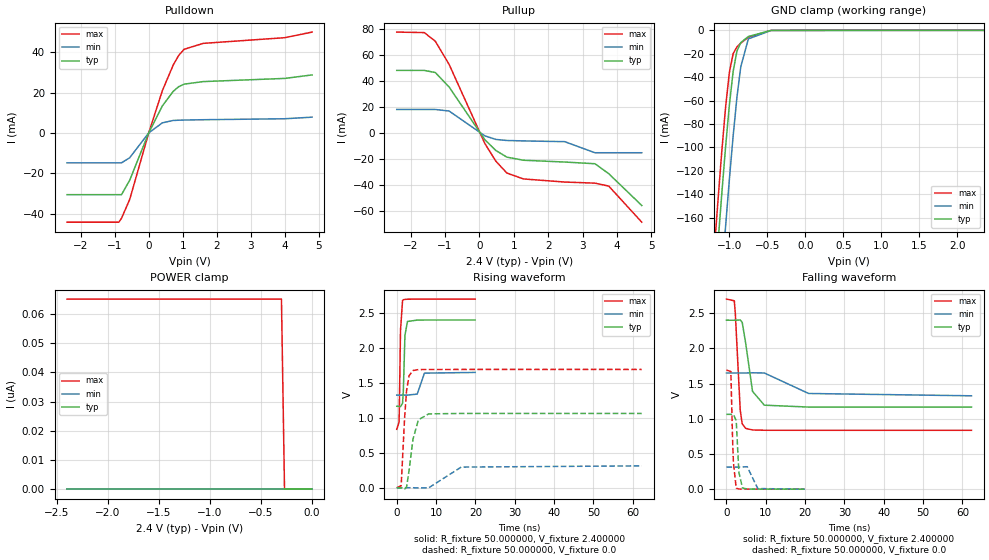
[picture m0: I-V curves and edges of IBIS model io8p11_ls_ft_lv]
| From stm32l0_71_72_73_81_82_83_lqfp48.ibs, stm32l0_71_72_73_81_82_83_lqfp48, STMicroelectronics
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|   Model io8p11_ls_ft_lv
[Model]  io8p11_ls_ft_lv
Model_type I/O
Polarity   Non-Inverting
Enable   Active-Low
Vinl =   0.720000V
Vinh =   1.680000V
Vmeas =  1.200000V
Cref =   50.000000pF
Rref =   100.000000M
Vref =   0.0V
C_comp   4.521100pF   4.438000pF   4.578000pF
[Temperature Range]   25.000000   0.105000k   -40.000000
[Pullup Reference]   2.400000V   1.650000V   2.700000V
[Pulldown Reference]   0.0V   0.0V   0.0V
[POWER Clamp Reference]   2.400000V   1.650000V   2.700000V
[GND Clamp Reference]   0.0V   0.0V   0.0V
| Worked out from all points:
|   slope of the pulldown table from 0 to 0.36 V, typ, clamps not added: 29.5 ohm
|   slope of the pullup table from 0 to 0.36 V, typ, clamps not added: 33.2 ohm
|   GND clamp passes 1 mA (typ) near -0.59 V on its own axis
|   rising waveform, R_fixture 50.000000, V_fixture 2.400000: 20-80 % time 364ps typ, 687ps min, 304ps max; typ from 1.17 V to 2.4 V
|   rising waveform, R_fixture 50.000000, V_fixture 0.0: 20-80 % time 1.63ns typ, 3.85ns min, 985ps max; typ from 0 V to 1.06 V
|   falling waveform, R_fixture 50.000000, V_fixture 2.400000: 20-80 % time 1.82ns typ, 5.38ns min, 983ps max; typ from 2.4 V to 1.17 V
|   falling waveform, R_fixture 50.000000, V_fixture 0.0: 20-80 % time 623ps typ, 1.01ns min, 516ps max; typ from 1.06 V to 0 V
[Pulldown]
|Voltage   I(typ)   I(min)   I(max)
-2.4V     -30.64mA   -14.84mA   -44.29mA
-880mV    -30.64mA   -14.84mA   -44.29mA
-800mV    -30.64mA   -14.84mA   -42.37mA
-560mV    -23.52mA   -12.34mA   -33.09mA
0V        -765.2nA   -61.1nA    -2.527uA
400mV     13.38mA    4.998mA    20.91mA
720mV     20.62mA    6.178mA    33.69mA
880mV     22.92mA    6.307mA    38.42mA
1.04V     24.19mA    6.385mA    41.49mA
1.6V      25.46mA    6.544mA    44.42mA
4V        27.04mA    7.029mA    47.25mA
4.8V      28.77mA    7.818mA    50.02mA
[Pullup]
|Voltage   I(typ)   I(min)   I(max)
-2.4V     48.08mA    17.97mA    77.6mA
-1.6V     48.08mA    17.97mA    77.22mA
-1.28V    46.45mA    17.97mA    70.55mA
-880mV    35.36mA    16.81mA    52.79mA
160mV     -5.286mA   -2.324mA   -8.223mA
480mV     -13.62mA   -5.103mA   -21.86mA
800mV     -18.73mA   -5.909mA   -31mA
1.28V     -21.13mA   -6.237mA   -35.54mA
2.48V     -22.51mA   -6.82mA    -37.93mA
3.36V     -23.83mA   -15.36mA   -38.77mA
3.76V     -31.5mA    -15.36mA   -41.06mA
4.72V     -56mA      -15.36mA   -68.86mA
[GND_clamp]
|Voltage   I(typ)   I(min)   I(max)
-2.4V     -1.379A    -1.445A    -1.35A
-1.2V     -225.9mA   -297.5mA   -189.2mA
-1.15V    -182mA     -253.1mA   -145.3mA
-1.1V     -139.6mA   -209.7mA   -103.5mA
-1.05V    -99.61mA   -167.6mA   -65.7mA
-1V       -63.67mA   -127.3mA   -35.89mA
-950mV    -35mA      -89.93mA   -19.87mA
-900mV    -17.67mA   -57.01mA   -14.12mA
-850mV    -10.49mA   -31.18mA   -11mA
-750mV    -5.288mA   -7.322mA   -5.997mA
-450mV    -33.57uA   -87.56uA   -14.35uA
2.35V     0A         0A         0A
[POWER_clamp]
|Voltage   I(typ)   I(min)   I(max)
-2.4V     0A         0A         65.17nA
-300mV    0A         0A         65.17nA
-270mV    0A         0A         0A
0V        0A         0A         0A
[Ramp]
| variable   typ   min   max
dV/dt_r  0.63779/1.62062n   0.18781/3.85012n   1.01572/0.97957n
dV/dt_f  0.74034/1.81656n   0.19290/5.36100n   1.11788/0.98038n
R_load = 50.000000
[Rising Waveform]
R_fixture= 50.000000
V_fixture= 2.400000
V_fixture_min= 1.650000
V_fixture_max= 2.700000
|time   V(typ)   V(min)   V(max)
0s        1.166V     1.326V     836.1mV
600.6ps   1.165V     1.326V     938.7mV
961ps     1.161V     1.326V     2.256V
1.481ns   1.21V      1.326V     2.679V
1.682ns   1.391V     1.326V     2.69V
2.082ns   2.179V     1.326V     2.695V
2.723ns   2.379V     1.326V     2.698V
5.205ns   2.399V     1.34V      2.699V
7.047ns   2.4V       1.64V      2.7V
19.94ns   2.4V       1.65V      2.7V
[Rising Waveform]
R_fixture= 50.000000
V_fixture= 0.0
V_fixture_min= 0.0
V_fixture_max= 0.0
|time   V(typ)   V(min)   V(max)
0s        63.35uV    12.7uV     531.9uV
1.126ns   -151.4uV   9.592uV    28.26mV
2.002ns   -20.43mV   22.6uV     1.001V
2.503ns   11.78mV    99.47uV    1.389V
3.128ns   243.6mV    98.53uV    1.602V
4.129ns   694.2mV    62.84uV    1.677V
5.506ns   971.6mV    -2.233mV   1.691V
8.133ns   1.057V     -668uV     1.692V
16.39ns   1.063V     295.5mV    1.693V
62.31ns   1.063V     313mV      1.693V
[Falling Waveform]
R_fixture= 50.000000
V_fixture= 2.400000
V_fixture_min= 1.650000
V_fixture_max= 2.700000
|time   V(typ)   V(min)   V(max)
0s        2.4V       1.65V      2.7V
2.002ns   2.399V     1.65V      2.675V
2.252ns   2.4V       1.65V      2.5V
3.504ns   2.403V     1.65V      1.122V
4.004ns   2.371V     1.65V      928.6mV
4.88ns    2.076V     1.65V      863.9mV
6.632ns   1.389V     1.653V     840.9mV
9.635ns   1.193V     1.65V      836.7mV
20.9ns    1.166V     1.359V     836.2mV
62.31ns   1.166V     1.326V     836.1mV
[Falling Waveform]
R_fixture= 50.000000
V_fixture= 0.0
V_fixture_min= 0.0
V_fixture_max= 0.0
|time   V(typ)   V(min)   V(max)
0s        1.063V     313mV      1.693V
1.121ns   1.063V     313mV      1.67V
1.522ns   1.062V     313mV      774mV
1.762ns   1.064V     313mV      386.7mV
2.482ns   974.1mV    313mV      13.59mV
3.163ns   239.4mV    312.7mV    2.841mV
4.084ns   16.78mV    315.6mV    1.81mV
5.285ns   1.895mV    318.8mV    1.07mV
7.968ns   543.9uV    8.55mV     653.6uV
19.94ns   63.35uV    12.7uV     531.9uV
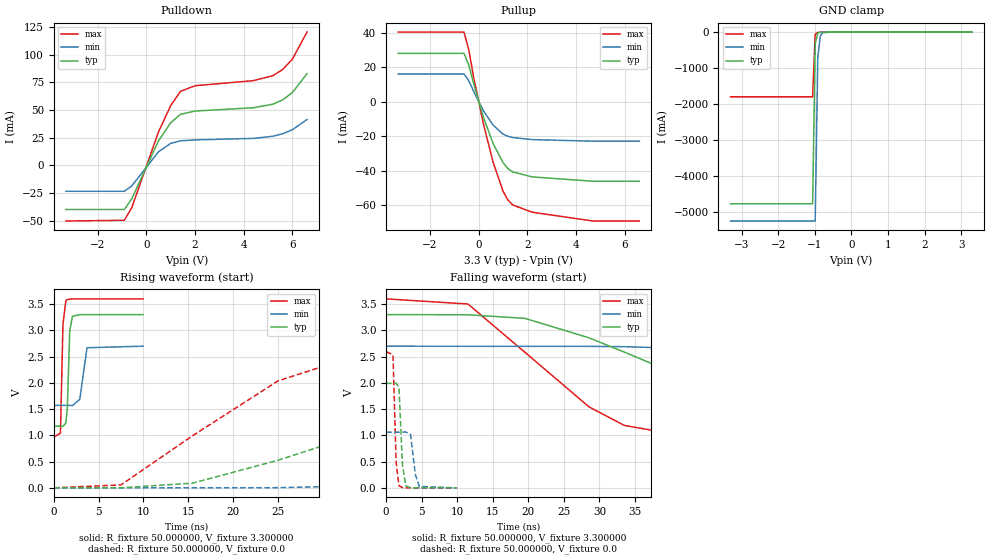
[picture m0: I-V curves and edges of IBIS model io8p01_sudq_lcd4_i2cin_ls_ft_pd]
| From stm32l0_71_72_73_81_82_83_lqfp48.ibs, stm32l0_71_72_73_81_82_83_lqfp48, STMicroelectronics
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|   Model io8p01_sudq_lcd4_i2cin_ls_ft_pd
[Model]  io8p01_sudq_lcd4_i2cin_ls_ft_pd
Model_type I/O
Polarity   Non-Inverting
Enable   Active-Low
Vinl =   0.990000V
Vinh =   2.310000V
Vmeas =  1.650000V
Cref =   50.000000pF
Rref =   100.000000M
Vref =   0.0V
C_comp   2.499500pF   2.460800pF   2.557800pF
[Temperature Range]   25.000000   0.125000k   -40.000000
[Pullup Reference]   3.300000V   2.700000V   3.600000V
[Pulldown Reference]   0.0V   0.0V   0.0V
[POWER Clamp Reference]   3.300000V   2.700000V   3.600000V
[GND Clamp Reference]   0.0V   0.0V   0.0V
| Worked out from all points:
|   slope of the pulldown table from 0 to 0.495 V, typ, clamps not added: 22.6 ohm
|   slope of the pullup table from 0 to 0.495 V, typ, clamps not added: 23.9 ohm
|   GND clamp passes 1 mA (typ) near -0.64 V on its own axis
|   rising waveform, R_fixture 50.000000, V_fixture 3.300000: 20-80 % time 216ps typ, 364ps min, 175ps max; typ from 1.18 V to 3.3 V
|   rising waveform, R_fixture 50.000000, V_fixture 0.0: 20-80 % time 27ns typ, 59.7ns min, 13.6ns max; typ from 0 V to 1.99 V
|   falling waveform, R_fixture 50.000000, V_fixture 3.300000: 20-80 % time 24.2ns typ, 53.2ns min, 13.3ns max; typ from 3.3 V to 1.18 V
|   falling waveform, R_fixture 50.000000, V_fixture 0.0: 20-80 % time 382ps typ, 550ps min, 305ps max; typ from 1.99 V to 0 V
[Pulldown]
|Voltage   I(typ)   I(min)   I(max)
-3.3V     -39.83mA   -23.36mA   -50.2mA
-900mV    -39.83mA   -23.36mA   -49.53mA
-600mV    -30.28mA   -18.59mA   -38.45mA
500mV     22.11mA    12.28mA    30.1mA
1V        38.33mA    19.81mA    53.88mA
1.4V      46.1mA     22.18mA    66.72mA
2V        49.07mA    23.02mA    71.93mA
4.4V      52.05mA    24.38mA    76.53mA
5.2V      55.25mA    26.3mA     81.02mA
5.6V      59.18mA    28.57mA    86.57mA
6V        65.78mA    32.24mA    95.96mA
6.6V      82.83mA    41.41mA    120.4mA
[Pullup]
|Voltage   I(typ)   I(min)   I(max)
-3.3V     27.97mA    16.07mA    40.33mA
-600mV    27.97mA    16.07mA    40.33mA
-400mV    21.07mA    12.09mA    29.9mA
-200mV    10.4mA     5.948mA    13.84mA
200mV     -9.115mA   -5.294mA   -12.98mA
600mV     -24.29mA   -13.56mA   -35.12mA
1V        -35.2mA    -18.69mA   -51.62mA
1.2V      -38.62mA   -19.99mA   -56.79mA
1.4V      -40.6mA    -20.72mA   -59.71mA
2.2V      -43.48mA   -21.92mA   -63.91mA
4.7V      -46mA      -22.8mA    -69mA
6.6V      -46mA      -22.8mA    -69mA
[GND_clamp]
|Voltage   I(typ)   I(min)   I(max)
-3.3V     -4.766A    -5.244A    -1.797A
-1.06V    -4.766A    -5.244A    -1.797A
-990mV    -326.4mA   -5.244A    -67.86mA
-920mV    -28.84mA   -721.7mA   -11.09mA
-850mV    -6.698mA   -104.1mA   -6.716mA
-780mV    -3.564mA   -17.3mA    -4.334mA
-500mV    -70.03uA   -187.2uA   -42.37uA
3.28V     73.94uA    88.61uA    51.47uA
[POWER_clamp]
|Voltage   I(typ)   I(min)   I(max)
-3.28V    0A         0A         0A
0V        0A         0A         0A
[Ramp]
| variable   typ   min   max
dV/dt_r  1.19406/27.01485n   0.63468/59.65625n   1.55520/13.55047n
dV/dt_f  1.27386/24.19846n   0.67098/53.12411n   1.57834/13.28722n
R_load = 50.000000
[Rising Waveform]
R_fixture= 50.000000
V_fixture= 3.300000
V_fixture_min= 2.700000
V_fixture_max= 3.600000
|time   V(typ)   V(min)   V(max)
0s        1.176V     1.571V     968.8mV
740.7ps   1.175V     1.571V     1.04V
1.021ns   1.172V     1.571V     3.119V
1.341ns   1.232V     1.571V     3.562V
1.502ns   1.499V     1.571V     3.586V
1.782ns   2.999V     1.57V      3.595V
2.082ns   3.266V     1.566V     3.597V
2.903ns   3.298V     1.686V     3.598V
3.704ns   3.298V     2.668V     3.598V
9.97ns    3.299V     2.698V     3.599V
[Rising Waveform]
R_fixture= 50.000000
V_fixture= 0.0
V_fixture_min= 0.0
V_fixture_max= 0.0
|time   V(typ)   V(min)   V(max)
0s        -596.6nV   -2.466uV   -308.2nV
7.508ns   -462.6uV   -168.3uV   56.08mV
15.52ns   89.73mV    -154.3uV   994.4mV
25.03ns   524.3mV    2.948mV    2.035V
31.03ns   854.7mV    24.65mV    2.366V
39.04ns   1.237V     73.89mV    2.522V
57.06ns   1.747V     273mV      2.583V
82.08ns   1.946V     591.7mV    2.592V
146.6ns   1.99V      988.1mV    2.592V
249.2ns   1.99V      1.06V      2.592V
[Falling Waveform]
R_fixture= 50.000000
V_fixture= 3.300000
V_fixture_min= 2.700000
V_fixture_max= 3.600000
|time   V(typ)   V(min)   V(max)
0s        3.299V     2.698V     3.599V
11.51ns   3.296V     2.695V     3.501V
19.52ns   3.228V     2.695V     2.582V
28.53ns   2.858V     2.695V     1.543V
33.53ns   2.584V     2.688V     1.187V
39.04ns   2.272V     2.666V     1.06V
56.06ns   1.481V     2.52V      987.3mV
76.58ns   1.26V      2.239V     973mV
123.6ns   1.187V     1.737V     969mV
249.2ns   1.176V     1.571V     968.8mV
[Falling Waveform]
R_fixture= 50.000000
V_fixture= 0.0
V_fixture_min= 0.0
V_fixture_max= 0.0
|time   V(typ)   V(min)   V(max)
0s        1.99V      1.06V      2.592V
961ps     1.99V      1.06V      2.535V
1.401ns   1.995V     1.06V      488.5mV
1.802ns   1.91V      1.06V      42.45mV
2.302ns   424.4mV    1.06V      2.61mV
2.763ns   38.45mV    1.064V     517.5uV
3.423ns   1.612mV    1.021V     202.4uV
4.104ns   303uV      256.5mV    102.3uV
4.665ns   181.6uV    27.67mV    60.85uV
9.97ns    -596.6nV   -2.466uV   -308.2nV
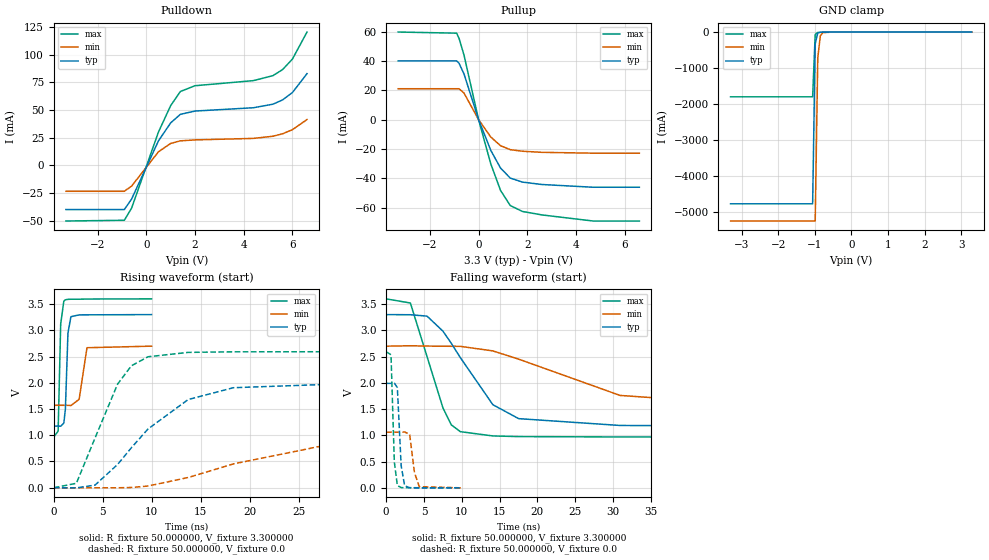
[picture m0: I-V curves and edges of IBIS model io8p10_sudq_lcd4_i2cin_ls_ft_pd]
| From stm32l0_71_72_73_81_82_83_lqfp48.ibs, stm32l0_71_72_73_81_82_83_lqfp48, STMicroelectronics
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|   Model io8p10_sudq_lcd4_i2cin_ls_ft_pd
[Model]  io8p10_sudq_lcd4_i2cin_ls_ft_pd
Model_type I/O
Polarity   Non-Inverting
Enable   Active-Low
Vinl =   0.990000V
Vinh =   2.310000V
Vmeas =  1.650000V
Cref =   50.000000pF
Rref =   100.000000M
Vref =   0.0V
C_comp   2.499500pF   2.460800pF   2.557800pF
[Temperature Range]   25.000000   0.125000k   -40.000000
[Pullup Reference]   3.300000V   2.700000V   3.600000V
[Pulldown Reference]   0.0V   0.0V   0.0V
[POWER Clamp Reference]   3.300000V   2.700000V   3.600000V
[GND Clamp Reference]   0.0V   0.0V   0.0V
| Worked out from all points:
|   slope of the pulldown table from 0 to 0.495 V, typ, clamps not added: 22.6 ohm
|   slope of the pullup table from 0 to 0.495 V, typ, clamps not added: 23.9 ohm
|   GND clamp passes 1 mA (typ) near -0.64 V on its own axis
|   rising waveform, R_fixture 50.000000, V_fixture 3.300000: 20-80 % time 216ps typ, 363ps min, 176ps max; typ from 1.18 V to 3.3 V
|   rising waveform, R_fixture 50.000000, V_fixture 0.0: 20-80 % time 6.51ns typ, 13.6ns min, 3.46ns max; typ from 0 V to 1.99 V
|   falling waveform, R_fixture 50.000000, V_fixture 3.300000: 20-80 % time 5.95ns typ, 12.6ns min, 3.27ns max; typ from 3.3 V to 1.18 V
|   falling waveform, R_fixture 50.000000, V_fixture 0.0: 20-80 % time 382ps typ, 550ps min, 305ps max; typ from 1.99 V to 0 V
[Pulldown]
|Voltage   I(typ)   I(min)   I(max)
-3.3V     -39.83mA   -23.36mA   -50.2mA
-900mV    -39.83mA   -23.36mA   -49.53mA
-600mV    -30.28mA   -18.59mA   -38.45mA
500mV     22.11mA    12.28mA    30.1mA
1V        38.33mA    19.81mA    53.88mA
1.4V      46.1mA     22.18mA    66.72mA
2V        49.07mA    23.02mA    71.93mA
4.4V      52.05mA    24.38mA    76.53mA
5.2V      55.25mA    26.31mA    81.02mA
5.6V      59.18mA    28.57mA    86.57mA
6V        65.78mA    32.24mA    95.96mA
6.6V      82.83mA    41.41mA    120.4mA
[Pullup]
|Voltage   I(typ)   I(min)   I(max)
-3.3V     40.02mA    21.08mA    59.7mA
-900mV    40.02mA    21.08mA    58.93mA
-800mV    38.37mA    21.08mA    55.25mA
-600mV    31.19mA    18.17mA    44.04mA
0V        0A         0A         0A
500mV     -20.88mA   -11.78mA   -30.07mA
900mV     -32.92mA   -17.72mA   -48.15mA
1.3V      -39.75mA   -20.41mA   -58.47mA
1.8V      -42.5mA    -21.48mA   -62.49mA
2.6V      -44.14mA   -22.23mA   -64.85mA
4.7V      -46mA      -22.8mA    -69mA
6.6V      -46mA      -22.8mA    -69mA
[GND_clamp]
|Voltage   I(typ)   I(min)   I(max)
-3.3V     -4.766A    -5.244A    -1.797A
-1.06V    -4.766A    -5.244A    -1.797A
-990mV    -326.4mA   -5.244A    -67.86mA
-920mV    -28.84mA   -721.7mA   -11.09mA
-850mV    -6.698mA   -104.1mA   -6.716mA
-780mV    -3.564mA   -17.3mA    -4.334mA
-500mV    -70.03uA   -187.2uA   -42.37uA
3.28V     73.94uA    88.61uA    51.47uA
[POWER_clamp]
|Voltage   I(typ)   I(min)   I(max)
-3.28V    0A         0A         0A
0V        0A         0A         0A
[Ramp]
| variable   typ   min   max
dV/dt_r  1.19412/6.49758n   0.62844/13.54598n   1.55520/3.45838n
dV/dt_f  1.27350/5.94381n   0.65388/12.51467n   1.57835/3.26031n
R_load = 50.000000
[Rising Waveform]
R_fixture= 50.000000
V_fixture= 3.300000
V_fixture_min= 2.700000
V_fixture_max= 3.600000
|time   V(typ)   V(min)   V(max)
0s        1.176V     1.571V     968.8mV
440.4ps   1.175V     1.571V     1.079V
700.7ps   1.172V     1.571V     3.119V
1.021ns   1.231V     1.571V     3.557V
1.181ns   1.5V       1.571V     3.581V
1.441ns   2.944V     1.57V      3.59V
1.742ns   3.259V     1.566V     3.592V
2.583ns   3.294V     1.686V     3.592V
3.383ns   3.295V     2.668V     3.596V
9.97ns    3.299V     2.698V     3.599V
[Rising Waveform]
R_fixture= 50.000000
V_fixture= 0.0
V_fixture_min= 0.0
V_fixture_max= 0.0
|time   V(typ)   V(min)   V(max)
0s        -98.2nV    -5.818uV   366.1uV
2.302ns   -2.077mV   -1.67mV    84.83mV
4.204ns   49.92mV    -865uV     947.7mV
6.507ns   443.5mV    -594.2uV   1.975V
7.908ns   760.9mV    4.472mV    2.323V
9.61ns    1.12V      32.51mV    2.496V
13.71ns   1.681V     194.8mV    2.579V
18.32ns   1.906V     453.9mV    2.59V
30.53ns   1.987V     916.1mV    2.592V
49.85ns   1.99V      1.06V      2.592V
[Falling Waveform]
R_fixture= 50.000000
V_fixture= 3.300000
V_fixture_min= 2.700000
V_fixture_max= 3.600000
|time   V(typ)   V(min)   V(max)
0s        3.299V     2.698V     3.599V
3.203ns   3.297V     2.706V     3.52V
5.405ns   3.27V      2.7V       2.5V
7.508ns   2.984V     2.697V     1.523V
8.609ns   2.753V     2.696V     1.2V
9.81ns    2.48V      2.695V     1.07V
14.11ns   1.583V     2.608V     988.4mV
17.52ns   1.318V     2.451V     976.1mV
30.93ns   1.188V     1.76V      969mV
49.85ns   1.176V     1.571V     968.8mV
[Falling Waveform]
R_fixture= 50.000000
V_fixture= 0.0
V_fixture_min= 0.0
V_fixture_max= 0.0
|time   V(typ)   V(min)   V(max)
0s        1.99V      1.06V      2.592V
640.6ps   1.99V      1.06V      2.535V
1.081ns   1.995V     1.06V      492.2mV
1.481ns   1.91V      1.06V      44.56mV
1.982ns   425.1mV    1.06V      4.857mV
2.442ns   39.07mV    1.064V     2.813mV
3.103ns   2.253mV    1.02V      2.6mV
3.744ns   1.028mV    287.9mV    2.898mV
4.384ns   924uV      22.47mV    1.964mV
9.97ns    -98.2nV    -5.818uV   366.1uV
